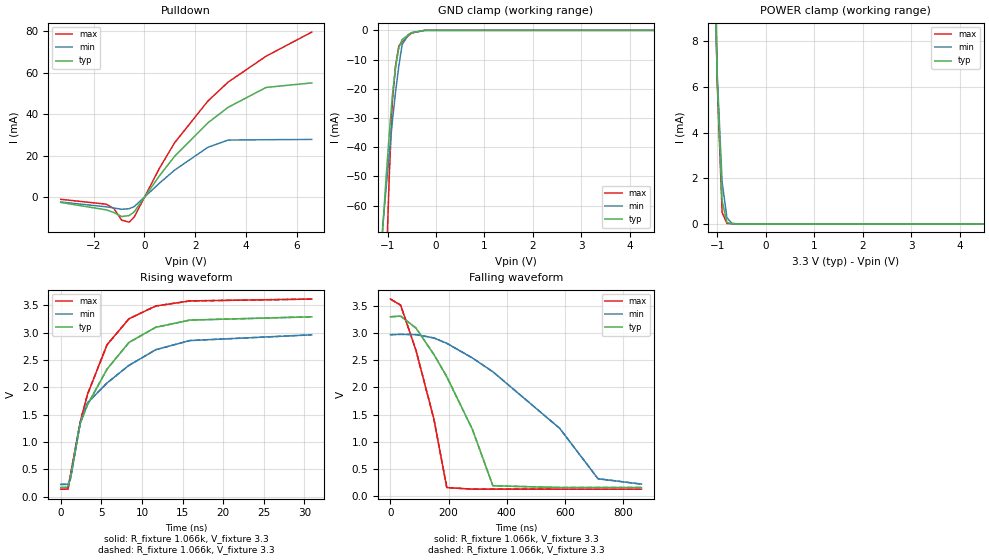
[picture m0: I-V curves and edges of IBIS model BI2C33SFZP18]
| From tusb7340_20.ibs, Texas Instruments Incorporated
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|   Model Cell BI2C33SFZP18
[Model]   BI2C33SFZP18
Model_type   I/O_open_drain
Polarity   Non-Inverting
Enable   Active-Low
Vinl =  0.99
Vinh =  2.31
Cref =  400pF
Rref =  528
Vref =  1.8V
Vmeas =  1.65
C_comp   1.455994p   1.366572p   1.486157p
[Model Spec]
Vinl   0.99   0.891   1.089
Vinh   2.31   2.079   2.541
[Temperature Range]   25   125   -40
[Voltage Range]   3.3   2.97   3.63
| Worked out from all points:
|   slope of the pulldown table from 0 to 0.495 V, typ, clamps not added: 56.9 ohm
|   GND clamp passes 1 mA (typ) near -0.52 V on its own axis
|   POWER clamp passes 1 mA (typ) near -0.90 V on its own axis
|   rising waveform, R_fixture 1.066k, V_fixture 3.3: 20-80 % time 5.65ns typ, 6.81ns min, 4.6ns max; typ from 0.164 V to 3.29 V
|   rising waveform, R_fixture 1.066k, V_fixture 3.3: 20-80 % time 5.65ns typ, 6.81ns min, 4.6ns max; typ from 0.164 V to 3.29 V
|   falling waveform, R_fixture 1.066k, V_fixture 3.3: 20-80 % time 171ns typ, 343ns min, 98.1ns max; typ from 3.3 V to 0.165 V
|   falling waveform, R_fixture 1.066k, V_fixture 3.3: 20-80 % time 171ns typ, 343ns min, 98.1ns max; typ from 3.3 V to 0.165 V
[POWER_clamp]
|   voltage   I(typ)   I(min)   I(max)
-3.3V     300.9mA    232.9mA    387.3mA
-1.033V   9.389mA    8.899mA    10.08mA
-1V       6.287mA    6.515mA    6.152mA
-900mV    1.015mA    1.832mA    502.1uA
-800mV    66.58uA    270.6uA    20.37uA
-700mV    7.102uA    32.1uA     8.903uA
-600mV    4.209uA    5.282uA    8.634uA
6.6V      0A         0A         0A
[Pulldown]
|   voltage   I(typ)   I(min)   I(max)
-3.3V     -2.467mA   -2.259mA   -966.9uA
-1.5V     -6.049mA   -4.582mA   -3.315mA
-1.2V     -7.309mA   -5.147mA   -5.389mA
-900mV    -9.264mA   -5.777mA   -10.98mA
-600mV    -8.794mA   -5.508mA   -11.98mA
-400mV    -6.99mA    -4.45mA    -9.457mA
600mV     10.47mA    6.863mA    14.15mA
1.2V      19.85mA    13.16mA    26.4mA
2.5V      35.82mA    24.05mA    46.29mA
3.3V      43.31mA    27.56mA    55.45mA
4.8V      52.9mA     27.72mA    67.94mA
6.6V      55.08mA    27.86mA    79.54mA
[GND_clamp]
|   voltage   I(typ)   I(min)   I(max)
-3.3V     -876.6mA   -765.7mA   -1.533A
-1.1V     -68.14mA   -67.16mA   -120.4mA
-1.033V   -51.31mA   -54.63mA   -83.88mA
-966.7mV  -36.03mA   -42.61mA   -50.99mA
-900mV    -22.29mA   -31.1mA    -24.19mA
-833.3mV  -12.31mA   -20.88mA   -12mA
-766.7mV  -5.94mA    -12.16mA   -5.386mA
-700mV    -3.186mA   -4.955mA   -4.077mA
-566.7mV  -1.504mA   -1.374mA   -1.789mA
-500mV    -791.9uA   -799.5uA   -943.8uA
-233.3mV  -5.528uA   -17.93uA   -1.129uA
6.6V      3.91uA     2.173uA    8.17uA
[Ramp]
| variable   typ   min   max
dV/dt_f   1.258975/0.1156448u   1.10146/0.2297404u   1.407272/66.55027n
dV/dt_r  0.1607937/0.2729562n  0.1228746/0.4594626n  0.1850558/0.1632436n
R_load = 1.066k
[Rising Waveform]
R_fixture = 1.066k
V_fixture = 3.3
V_fixture_min = 2.97
V_fixture_max = 3.63
|   time   V(typ)   V(min)   V(max)
0s        164.2mV    221mV      134.4mV
900ps     168.2mV    223.3mV    135mV
1.2ns     359.4mV    318.7mV    393.9mV
2.4ns     1.342V     1.345V     1.363V
3.3ns     1.68V      1.716V     1.873V
5.7ns     2.333V     2.08V      2.779V
8.4ns     2.822V     2.402V     3.256V
11.7ns    3.1V       2.689V     3.49V
15.9ns    3.232V     2.857V     3.583V
30.9ns    3.292V     2.962V     3.617V
[Rising Waveform]
R_fixture = 1.066k
V_fixture = 3.3
V_fixture_min = 2.97
V_fixture_max = 3.63
|   time   V(typ)   V(min)   V(max)
0s        164.2mV    221mV      134.4mV
900ps     168.2mV    223.3mV    135mV
1.2ns     359.4mV    318.7mV    393.9mV
2.4ns     1.342V     1.345V     1.363V
3.3ns     1.68V      1.716V     1.873V
5.7ns     2.333V     2.08V      2.779V
8.4ns     2.822V     2.402V     3.256V
11.7ns    3.1V       2.689V     3.49V
15.9ns    3.232V     2.857V     3.583V
30.9ns    3.292V     2.962V     3.617V
[Falling Waveform]
R_fixture = 1.066k
V_fixture = 3.3
V_fixture_min = 2.97
V_fixture_max = 3.63
|   time   V(typ)   V(min)   V(max)
0s        3.296V     2.968V     3.621V
35.1ns    3.308V     2.974V     3.51V
87.9ns    3.089V     2.969V     2.68V
149.7ns   2.603V     2.908V     1.415V
193.8ns   2.196V     2.809V     163.3mV
281.7ns   1.233V     2.541V     134.6mV
352.2ns   196.4mV    2.288V     134.5mV
581.7ns   164.7mV    1.251V     134.5mV
713.7ns   164.6mV    325.7mV    134.4mV
863.1ns   164.5mV    227mV      134.4mV
[Falling Waveform]
R_fixture = 1.066k
V_fixture = 3.3
V_fixture_min = 2.97
V_fixture_max = 3.63
|   time   V(typ)   V(min)   V(max)
0s        3.296V     2.968V     3.621V
35.1ns    3.308V     2.974V     3.51V
87.9ns    3.089V     2.969V     2.68V
149.7ns   2.603V     2.908V     1.415V
193.8ns   2.196V     2.809V     163.3mV
281.7ns   1.233V     2.541V     134.6mV
352.2ns   196.4mV    2.288V     134.5mV
581.7ns   164.7mV    1.251V     134.5mV
713.7ns   164.6mV    325.7mV    134.4mV
863.1ns   164.5mV    227mV      134.4mV
